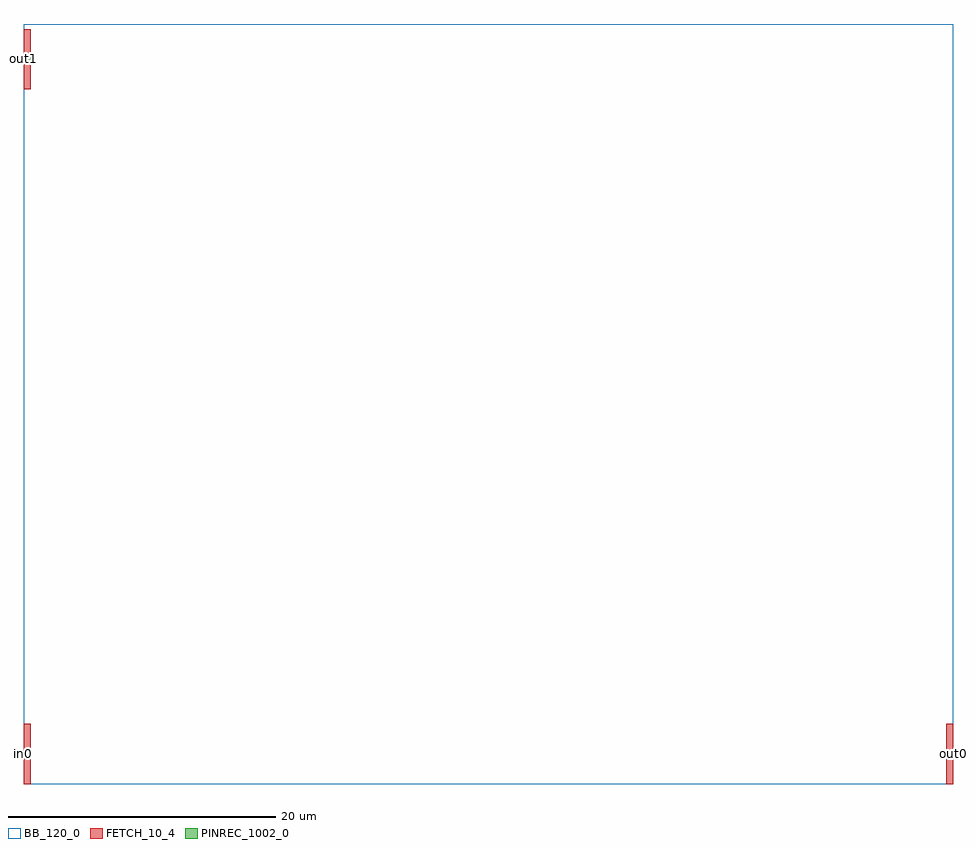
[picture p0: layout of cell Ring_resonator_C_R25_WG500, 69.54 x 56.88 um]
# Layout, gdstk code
import gdstk
lib = gdstk.Library(unit=1e-6, precision=1e-09)
def R(c, l, rs):  # rectangles x0, y0, x1, y1
    for r in rs: c.add(gdstk.rectangle(r[:2], r[2:], *l))
FETCH_10_4 = (10, 4)
BB_120_0 = (120, 0)
PINREC_1002_0 = (1002, 0)

ring_resonator_c_r25_wg5 = lib.new_cell('Ring_resonator_C_R25_WG500')
R(ring_resonator_c_r25_wg5, FETCH_10_4, [(0,0,0.5,2), (69.042,0,69.542,2), (0,2.5,0.5,4.5), (69.042,2.5,69.542,4.5), (0,52,0.5,54), (0,54.5,0.5,56.5)])
R(ring_resonator_c_r25_wg5, BB_120_0, [(0,0,69.542,56.875)])
R(ring_resonator_c_r25_wg5, PINREC_1002_0, [(0,2,0.5,2.5), (69.042,2,69.542,2.5), (0,54,0.5,54.5)])
ring_resonator_c_r25_wg5.add(gdstk.Label('out0', (69.542,2.269), layer=1000, texttype=0))
ring_resonator_c_r25_wg5.add(gdstk.Label('in0', (0,2.263), layer=1000, texttype=0))
ring_resonator_c_r25_wg5.add(gdstk.Label('out1', (0,54.269), layer=1000, texttype=0))

lib.write_gds('Ring_resonator_C_R25_WG500.gds')
